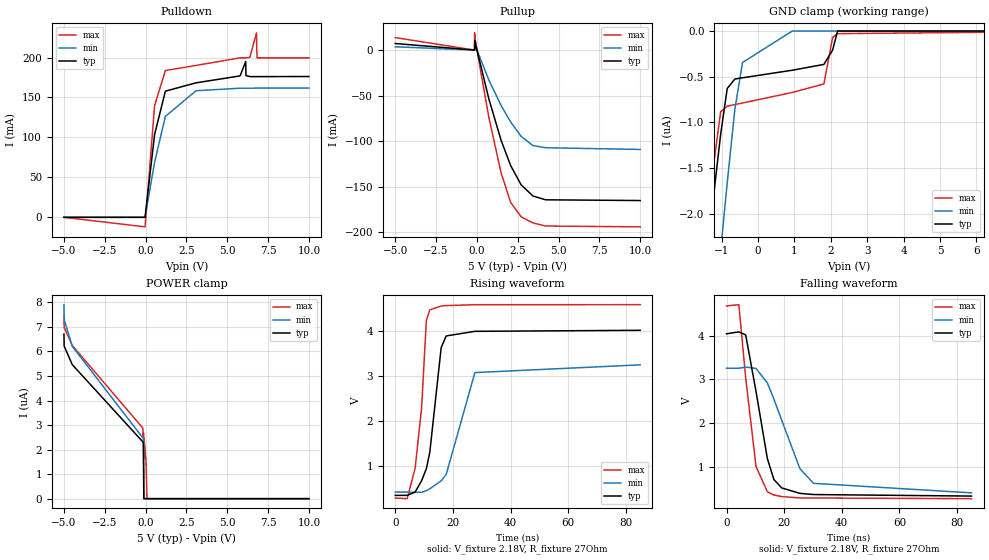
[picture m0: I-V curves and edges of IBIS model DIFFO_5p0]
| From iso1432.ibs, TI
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|   DIFFO_5p0 Model
[Model]   DIFFO_5p0
Model_type   3-state
Polarity   Non-Inverting
Vmeas = 2.1804
Vref = 2.1804
Cref = 2pF
Rref = 27
|   typ   min   max
C_comp   24.190pF   23.315pF   24.754pF
|  Where Nom  PVT is Nominal Process, 5.0V,   27C
|   Fast PVT is Strong Process,  5.5V,   -40C
|   Slow PVT is Weak Process,   4.5V,   150C
[Voltage Range]   5   4.5   5.5
|Junction Temperature
[Temperature Range]   27   150   -40
[Pullup Reference]   5   4.5   5.5
[Pulldown Reference]   0   -0   0
[Power Clamp Reference]   5   4.5   5.5
[GND Clamp Reference]   0   0   0
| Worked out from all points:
|   slope of the pulldown table from 0 to 0.75 V, typ, clamps not added: 5.76 ohm
|   slope of the pullup table from 0 to 0.75 V, typ, clamps not added: 13.7 ohm
|   falling waveform, V_fixture 2.18V, R_fixture 27Ohm: 20-80 % time 5.83ns typ, 9.72ns min, 4.28ns max; typ from 4.04 V to 0.335 V
|   rising waveform, V_fixture 2.18V, R_fixture 27Ohm: 20-80 % time 3.92ns typ, 6.05ns min, 2.89ns max; typ from 0.335 V to 4.03 V
[Pulldown]
|   Voltage   I(typ)   I(min)   I(max)
-5V       -2.768nA   -62.36nA   -404.6pA
-35mV     425.7nA    561.8nA    -11.95mA
550mV     103.6mA    68.78mA    139.8mA
1.21V     157.9mA    126.3mA    183.7mA
3.085V    168.3mA    158.4mA    190.1mA
5.785V    177mA      161.6mA    199.6mA
6.13V     195mA      161.6mA    199.6mA
6.145V    177.4mA    161.6mA    199.6mA
6.385V    176.1mA    161.6mA    200.3mA
6.79V     176.1mA    161.7mA    230.9mA
6.82V     176.1mA    161.7mA    199.6mA
10V       176.2mA    161.8mA    199.6mA
[GND Clamp]
|   Voltage   I(typ)   I(min)   I(max)
-5V       -16.78uA   -20.83uA   -17.26uA
-1.595V   -3.188uA   -4.867uA   -2.896uA
-1.235V   -1.86uA    -3.297uA   -1.512uA
-1.025V   -1.13uA    -2.4uA     -883.3nA
-845mV    -629.1nA   -1.663uA   -821.7nA
-635mV    -525.4nA   -857.6nA   -804.5nA
-425mV    -511.6nA   -344.6nA   -787.4nA
940mV     -428.9nA   0A         -672.2nA
1.81V     -365.2nA   0A         -578.8nA
2.05V     -208.4nA   0A         -69.8nA
2.185V    0A         0A         -28.58nA
10V       0A         0A         0A
[Pullup]
|   Voltage   I(typ)   I(min)   I(max)
-5V       7.291mA    3.674mA    13.77mA
-155mV    86.47uA    72.78uA    97.97uA
-140mV    85.13uA    71.46uA    19mA
-110mV    10.38mA    68.93uA    12.14mA
-80mV     6.406mA    4.087mA    8.83mA
730mV     -53.41mA   -32.72mA   -73.7mA
1.48V     -98.98mA   -60.78mA   -134.7mA
2.065V    -126.7mA   -78.83mA   -167.2mA
2.71V     -148mA     -94.69mA   -183.1mA
3.43V     -160.2mA   -104.8mA   -189.8mA
4.21V     -164.4mA   -107.2mA   -193.2mA
10V       -165.2mA   -109.1mA   -194.1mA
[POWER Clamp]
|   Voltage   I(typ)   I(min)   I(max)
-5V       6.707uA    7.907uA    7.452uA
-4.985V   6.207uA    7.35uA     6.964uA
-4.955V   6.169uA    7.231uA    6.928uA
-4.49V    5.462uA    6.208uA    6.245uA
-170mV    2.316uA    2.479uA    2.877uA
-140mV    2.258uA    2.42uA     2.554uA
-125mV    1.129uA    2.383uA    2.672uA
-110mV    0A         1.192uA    1.651uA
-95mV     0A         0A         2.475uA
25mV      0A         0A         1.542uA
85mV      0A         0A         0A
10V       0A         0A         0A
[Ramp]
R_load = 27
|   typ   min   max
dV/dt_r   2.21393/3.91493e-09   1.70665/6.00672e-09   2.59321/2.86941e-09
dV/dt_f   2.22319/5.82596e-09   1.70766/9.70212e-09   2.64049/4.27754e-09
[Falling Waveform]
V_fixture = 2.18V
V_fixture_min = 1.83V
V_fixture_max = 2.441V
R_fixture = 27Ohm
C_fixture = 0F
|   Time   V(typ)   V(min)   V(max)
0s        4.041V     3.255V     4.677V
4.27ns    4.084V     3.254V     4.706V
6.651ns   4.015V     3.281V     3.035V
10.22ns   2.73V      3.25V      1.014V
14.17ns   1.192V     2.919V     432mV
16.43ns   713.4mV    2.551V     360.1mV
19.14ns   521.7mV    2.069V     324mV
25.45ns   397.6mV    962.2mV    292.7mV
30.18ns   370.3mV    626.4mV    291.3mV
85ns      335.4mV    408.9mV    275.9mV
[Rising Waveform]
V_fixture = 2.18V
V_fixture_min = 1.83V
V_fixture_max = 2.441V
R_fixture = 27Ohm
C_fixture = 0F
|   Time   V(typ)   V(min)   V(max)
0s        335.3mV    408.8mV    275.8mV
4.14ns    335.8mV    408.9mV    261.4mV
6.914ns   409.1mV    403.9mV    945.4mV
9.153ns   664.6mV    403.9mV    2.295V
10.8ns    931.4mV    440mV      4.245V
11.99ns   1.297V     483.1mV    4.481V
15.94ns   3.638V     660.7mV    4.569V
17.68ns   3.899V     801.7mV    4.577V
27.64ns   4.002V     3.08V      4.597V
85ns      4.025V     3.253V     4.598V
